VERSION 5.7 ;
  NOWIREEXTENSIONATPIN ON ;
  DIVIDERCHAR "/" ;
  BUSBITCHARS "[]" ;
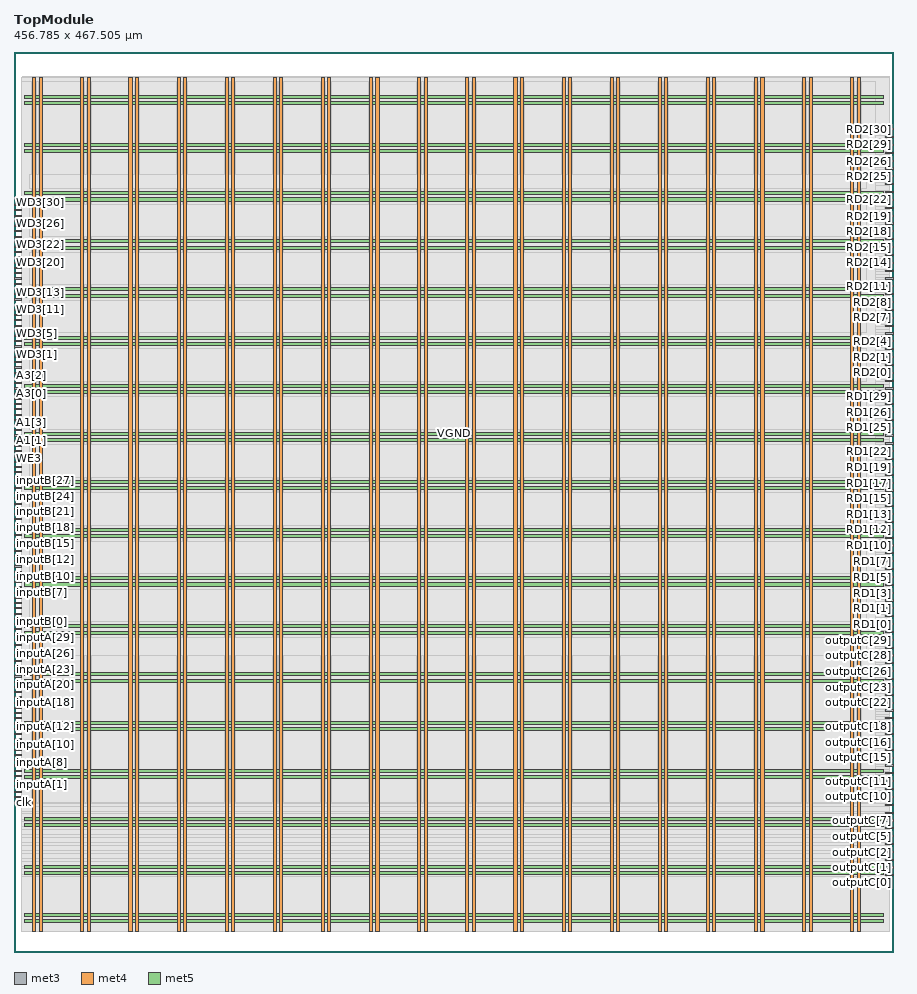
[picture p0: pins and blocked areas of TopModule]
MACRO TopModule
  CLASS BLOCK ;
  FOREIGN TopModule ;
  ORIGIN 0.000 0.000 ;
  SIZE 456.785 BY 467.505 ;
  PIN A1[0]
    DIRECTION INPUT ;
    USE SIGNAL ;
    ANTENNAGATEAREA 2.446500 ;
    PORT
      LAYER met3 ;
        RECT 0.000 262.520 4.000 263.120 ;
    END
  END A1[0]
  PIN A1[1]
    DIRECTION INPUT ;
    USE SIGNAL ;
    ANTENNAGATEAREA 1.560000 ;
    ANTENNADIFFAREA 0.434700 ;
    PORT
      LAYER met3 ;
        RECT 0.000 265.240 4.000 265.840 ;
    END
  END A1[1]
  PIN A1[2]
    DIRECTION INPUT ;
    USE SIGNAL ;
    ANTENNAGATEAREA 0.159000 ;
    PORT
      LAYER met3 ;
        RECT 0.000 267.960 4.000 268.560 ;
    END
  END A1[2]
  PIN A1[3]
    DIRECTION INPUT ;
    USE SIGNAL ;
    ANTENNAGATEAREA 0.247500 ;
    PORT
      LAYER met3 ;
        RECT 0.000 270.680 4.000 271.280 ;
    END
  END A1[3]
  PIN A1[4]
    DIRECTION INPUT ;
    USE SIGNAL ;
    ANTENNAGATEAREA 0.495000 ;
    PORT
      LAYER met3 ;
        RECT 0.000 273.400 4.000 274.000 ;
    END
  END A1[4]
  PIN A2[0]
    DIRECTION INPUT ;
    USE SIGNAL ;
    ANTENNAGATEAREA 0.247500 ;
    PORT
      LAYER met3 ;
        RECT 0.000 276.120 4.000 276.720 ;
    END
  END A2[0]
  PIN A2[1]
    DIRECTION INPUT ;
    USE SIGNAL ;
    ANTENNAGATEAREA 0.213000 ;
    PORT
      LAYER met3 ;
        RECT 0.000 278.840 4.000 279.440 ;
    END
  END A2[1]
  PIN A2[2]
    DIRECTION INPUT ;
    USE SIGNAL ;
    ANTENNAGATEAREA 0.159000 ;
    PORT
      LAYER met3 ;
        RECT 0.000 281.560 4.000 282.160 ;
    END
  END A2[2]
  PIN A2[3]
    DIRECTION INPUT ;
    USE SIGNAL ;
    ANTENNAGATEAREA 0.426000 ;
    PORT
      LAYER met3 ;
        RECT 0.000 284.280 4.000 284.880 ;
    END
  END A2[3]
  PIN A2[4]
    DIRECTION INPUT ;
    USE SIGNAL ;
    ANTENNAGATEAREA 0.495000 ;
    PORT
      LAYER met3 ;
        RECT 0.000 287.000 4.000 287.600 ;
    END
  END A2[4]
  PIN A3[0]
    DIRECTION INPUT ;
    USE SIGNAL ;
    ANTENNAGATEAREA 0.247500 ;
    PORT
      LAYER met3 ;
        RECT 0.000 289.720 4.000 290.320 ;
    END
  END A3[0]
  PIN A3[1]
    DIRECTION INPUT ;
    USE SIGNAL ;
    ANTENNAGATEAREA 0.213000 ;
    PORT
      LAYER met3 ;
        RECT 0.000 292.440 4.000 293.040 ;
    END
  END A3[1]
  PIN A3[2]
    DIRECTION INPUT ;
    USE SIGNAL ;
    ANTENNAGATEAREA 0.213000 ;
    PORT
      LAYER met3 ;
        RECT 0.000 295.160 4.000 295.760 ;
    END
  END A3[2]
  PIN A3[3]
    DIRECTION INPUT ;
    USE SIGNAL ;
    ANTENNAGATEAREA 0.213000 ;
    PORT
      LAYER met3 ;
        RECT 0.000 297.880 4.000 298.480 ;
    END
  END A3[3]
  PIN A3[4]
    DIRECTION INPUT ;
    USE SIGNAL ;
    ANTENNAGATEAREA 0.213000 ;
    PORT
      LAYER met3 ;
        RECT 0.000 300.600 4.000 301.200 ;
    END
  END A3[4]
  PIN RD1[0]
    DIRECTION OUTPUT ;
    USE SIGNAL ;
    ANTENNADIFFAREA 0.445500 ;
    PORT
      LAYER met3 ;
        RECT 452.785 170.040 456.785 170.640 ;
    END
  END RD1[0]
  PIN RD1[10]
    DIRECTION OUTPUT ;
    USE SIGNAL ;
    ANTENNADIFFAREA 0.445500 ;
    PORT
      LAYER met3 ;
        RECT 452.785 210.840 456.785 211.440 ;
    END
  END RD1[10]
  PIN RD1[11]
    DIRECTION OUTPUT ;
    USE SIGNAL ;
    ANTENNADIFFAREA 0.445500 ;
    PORT
      LAYER met3 ;
        RECT 452.785 214.920 456.785 215.520 ;
    END
  END RD1[11]
  PIN RD1[12]
    DIRECTION OUTPUT ;
    USE SIGNAL ;
    ANTENNADIFFAREA 0.445500 ;
    PORT
      LAYER met3 ;
        RECT 452.785 219.000 456.785 219.600 ;
    END
  END RD1[12]
  PIN RD1[13]
    DIRECTION OUTPUT ;
    USE SIGNAL ;
    ANTENNADIFFAREA 0.445500 ;
    PORT
      LAYER met3 ;
        RECT 452.785 223.080 456.785 223.680 ;
    END
  END RD1[13]
  PIN RD1[14]
    DIRECTION OUTPUT ;
    USE SIGNAL ;
    ANTENNADIFFAREA 0.445500 ;
    PORT
      LAYER met3 ;
        RECT 452.785 227.160 456.785 227.760 ;
    END
  END RD1[14]
  PIN RD1[15]
    DIRECTION OUTPUT ;
    USE SIGNAL ;
    ANTENNADIFFAREA 0.445500 ;
    PORT
      LAYER met3 ;
        RECT 452.785 231.240 456.785 231.840 ;
    END
  END RD1[15]
  PIN RD1[16]
    DIRECTION OUTPUT ;
    USE SIGNAL ;
    ANTENNADIFFAREA 0.445500 ;
    PORT
      LAYER met3 ;
        RECT 452.785 235.320 456.785 235.920 ;
    END
  END RD1[16]
  PIN RD1[17]
    DIRECTION OUTPUT ;
    USE SIGNAL ;
    ANTENNADIFFAREA 0.445500 ;
    PORT
      LAYER met3 ;
        RECT 452.785 239.400 456.785 240.000 ;
    END
  END RD1[17]
  PIN RD1[18]
    DIRECTION OUTPUT ;
    USE SIGNAL ;
    ANTENNADIFFAREA 0.445500 ;
    PORT
      LAYER met3 ;
        RECT 452.785 243.480 456.785 244.080 ;
    END
  END RD1[18]
  PIN RD1[19]
    DIRECTION OUTPUT ;
    USE SIGNAL ;
    ANTENNADIFFAREA 0.445500 ;
    PORT
      LAYER met3 ;
        RECT 452.785 247.560 456.785 248.160 ;
    END
  END RD1[19]
  PIN RD1[1]
    DIRECTION OUTPUT ;
    USE SIGNAL ;
    ANTENNADIFFAREA 0.445500 ;
    PORT
      LAYER met3 ;
        RECT 452.785 174.120 456.785 174.720 ;
    END
  END RD1[1]
  PIN RD1[20]
    DIRECTION OUTPUT ;
    USE SIGNAL ;
    ANTENNADIFFAREA 0.445500 ;
    PORT
      LAYER met3 ;
        RECT 452.785 251.640 456.785 252.240 ;
    END
  END RD1[20]
  PIN RD1[21]
    DIRECTION OUTPUT ;
    USE SIGNAL ;
    ANTENNADIFFAREA 0.445500 ;
    PORT
      LAYER met3 ;
        RECT 452.785 255.720 456.785 256.320 ;
    END
  END RD1[21]
  PIN RD1[22]
    DIRECTION OUTPUT ;
    USE SIGNAL ;
    ANTENNADIFFAREA 0.445500 ;
    PORT
      LAYER met3 ;
        RECT 452.785 259.800 456.785 260.400 ;
    END
  END RD1[22]
  PIN RD1[23]
    DIRECTION OUTPUT ;
    USE SIGNAL ;
    ANTENNADIFFAREA 0.445500 ;
    PORT
      LAYER met3 ;
        RECT 452.785 263.880 456.785 264.480 ;
    END
  END RD1[23]
  PIN RD1[24]
    DIRECTION OUTPUT ;
    USE SIGNAL ;
    ANTENNADIFFAREA 0.445500 ;
    PORT
      LAYER met3 ;
        RECT 452.785 267.960 456.785 268.560 ;
    END
  END RD1[24]
  PIN RD1[25]
    DIRECTION OUTPUT ;
    USE SIGNAL ;
    ANTENNADIFFAREA 0.445500 ;
    PORT
      LAYER met3 ;
        RECT 452.785 272.040 456.785 272.640 ;
    END
  END RD1[25]
  PIN RD1[26]
    DIRECTION OUTPUT ;
    USE SIGNAL ;
    ANTENNADIFFAREA 0.445500 ;
    PORT
      LAYER met3 ;
        RECT 452.785 276.120 456.785 276.720 ;
    END
  END RD1[26]
  PIN RD1[27]
    DIRECTION OUTPUT ;
    USE SIGNAL ;
    ANTENNADIFFAREA 0.445500 ;
    PORT
      LAYER met3 ;
        RECT 452.785 280.200 456.785 280.800 ;
    END
  END RD1[27]
  PIN RD1[28]
    DIRECTION OUTPUT ;
    USE SIGNAL ;
    ANTENNADIFFAREA 0.445500 ;
    PORT
      LAYER met3 ;
        RECT 452.785 284.280 456.785 284.880 ;
    END
  END RD1[28]
  PIN RD1[29]
    DIRECTION OUTPUT ;
    USE SIGNAL ;
    ANTENNADIFFAREA 0.445500 ;
    PORT
      LAYER met3 ;
        RECT 452.785 288.360 456.785 288.960 ;
    END
  END RD1[29]
  PIN RD1[2]
    DIRECTION OUTPUT ;
    USE SIGNAL ;
    ANTENNADIFFAREA 0.445500 ;
    PORT
      LAYER met3 ;
        RECT 452.785 178.200 456.785 178.800 ;
    END
  END RD1[2]
  PIN RD1[30]
    DIRECTION OUTPUT ;
    USE SIGNAL ;
    ANTENNADIFFAREA 0.445500 ;
    PORT
      LAYER met3 ;
        RECT 452.785 292.440 456.785 293.040 ;
    END
  END RD1[30]
  PIN RD1[31]
    DIRECTION OUTPUT ;
    USE SIGNAL ;
    ANTENNADIFFAREA 0.445500 ;
    PORT
      LAYER met3 ;
        RECT 452.785 296.520 456.785 297.120 ;
    END
  END RD1[31]
  PIN RD1[3]
    DIRECTION OUTPUT ;
    USE SIGNAL ;
    ANTENNADIFFAREA 0.445500 ;
    PORT
      LAYER met3 ;
        RECT 452.785 182.280 456.785 182.880 ;
    END
  END RD1[3]
  PIN RD1[4]
    DIRECTION OUTPUT ;
    USE SIGNAL ;
    ANTENNADIFFAREA 0.445500 ;
    PORT
      LAYER met3 ;
        RECT 452.785 186.360 456.785 186.960 ;
    END
  END RD1[4]
  PIN RD1[5]
    DIRECTION OUTPUT ;
    USE SIGNAL ;
    ANTENNADIFFAREA 0.445500 ;
    PORT
      LAYER met3 ;
        RECT 452.785 190.440 456.785 191.040 ;
    END
  END RD1[5]
  PIN RD1[6]
    DIRECTION OUTPUT ;
    USE SIGNAL ;
    ANTENNADIFFAREA 0.445500 ;
    PORT
      LAYER met3 ;
        RECT 452.785 194.520 456.785 195.120 ;
    END
  END RD1[6]
  PIN RD1[7]
    DIRECTION OUTPUT ;
    USE SIGNAL ;
    ANTENNADIFFAREA 0.445500 ;
    PORT
      LAYER met3 ;
        RECT 452.785 198.600 456.785 199.200 ;
    END
  END RD1[7]
  PIN RD1[8]
    DIRECTION OUTPUT ;
    USE SIGNAL ;
    ANTENNADIFFAREA 0.445500 ;
    PORT
      LAYER met3 ;
        RECT 452.785 202.680 456.785 203.280 ;
    END
  END RD1[8]
  PIN RD1[9]
    DIRECTION OUTPUT ;
    USE SIGNAL ;
    ANTENNADIFFAREA 0.445500 ;
    PORT
      LAYER met3 ;
        RECT 452.785 206.760 456.785 207.360 ;
    END
  END RD1[9]
  PIN RD2[0]
    DIRECTION OUTPUT ;
    USE SIGNAL ;
    ANTENNADIFFAREA 0.445500 ;
    PORT
      LAYER met3 ;
        RECT 452.785 300.600 456.785 301.200 ;
    END
  END RD2[0]
  PIN RD2[10]
    DIRECTION OUTPUT ;
    USE SIGNAL ;
    ANTENNADIFFAREA 0.445500 ;
    PORT
      LAYER met3 ;
        RECT 452.785 341.400 456.785 342.000 ;
    END
  END RD2[10]
  PIN RD2[11]
    DIRECTION OUTPUT ;
    USE SIGNAL ;
    ANTENNADIFFAREA 0.445500 ;
    PORT
      LAYER met3 ;
        RECT 452.785 345.480 456.785 346.080 ;
    END
  END RD2[11]
  PIN RD2[12]
    DIRECTION OUTPUT ;
    USE SIGNAL ;
    ANTENNADIFFAREA 0.445500 ;
    PORT
      LAYER met3 ;
        RECT 452.785 349.560 456.785 350.160 ;
    END
  END RD2[12]
  PIN RD2[13]
    DIRECTION OUTPUT ;
    USE SIGNAL ;
    ANTENNADIFFAREA 0.445500 ;
    PORT
      LAYER met3 ;
        RECT 452.785 353.640 456.785 354.240 ;
    END
  END RD2[13]
  PIN RD2[14]
    DIRECTION OUTPUT ;
    USE SIGNAL ;
    ANTENNADIFFAREA 0.445500 ;
    PORT
      LAYER met3 ;
        RECT 452.785 357.720 456.785 358.320 ;
    END
  END RD2[14]
  PIN RD2[15]
    DIRECTION OUTPUT ;
    USE SIGNAL ;
    ANTENNADIFFAREA 0.445500 ;
    PORT
      LAYER met3 ;
        RECT 452.785 361.800 456.785 362.400 ;
    END
  END RD2[15]
  PIN RD2[16]
    DIRECTION OUTPUT ;
    USE SIGNAL ;
    ANTENNADIFFAREA 0.445500 ;
    PORT
      LAYER met3 ;
        RECT 452.785 365.880 456.785 366.480 ;
    END
  END RD2[16]
  PIN RD2[17]
    DIRECTION OUTPUT ;
    USE SIGNAL ;
    ANTENNADIFFAREA 0.445500 ;
    PORT
      LAYER met3 ;
        RECT 452.785 369.960 456.785 370.560 ;
    END
  END RD2[17]
  PIN RD2[18]
    DIRECTION OUTPUT ;
    USE SIGNAL ;
    ANTENNADIFFAREA 0.445500 ;
    PORT
      LAYER met3 ;
        RECT 452.785 374.040 456.785 374.640 ;
    END
  END RD2[18]
  PIN RD2[19]
    DIRECTION OUTPUT ;
    USE SIGNAL ;
    ANTENNADIFFAREA 0.445500 ;
    PORT
      LAYER met3 ;
        RECT 452.785 378.120 456.785 378.720 ;
    END
  END RD2[19]
  PIN RD2[1]
    DIRECTION OUTPUT ;
    USE SIGNAL ;
    ANTENNADIFFAREA 0.445500 ;
    PORT
      LAYER met3 ;
        RECT 452.785 304.680 456.785 305.280 ;
    END
  END RD2[1]
  PIN RD2[20]
    DIRECTION OUTPUT ;
    USE SIGNAL ;
    ANTENNADIFFAREA 0.445500 ;
    PORT
      LAYER met3 ;
        RECT 452.785 382.200 456.785 382.800 ;
    END
  END RD2[20]
  PIN RD2[21]
    DIRECTION OUTPUT ;
    USE SIGNAL ;
    ANTENNADIFFAREA 0.445500 ;
    PORT
      LAYER met3 ;
        RECT 452.785 386.280 456.785 386.880 ;
    END
  END RD2[21]
  PIN RD2[22]
    DIRECTION OUTPUT ;
    USE SIGNAL ;
    ANTENNADIFFAREA 0.445500 ;
    PORT
      LAYER met3 ;
        RECT 452.785 390.360 456.785 390.960 ;
    END
  END RD2[22]
  PIN RD2[23]
    DIRECTION OUTPUT ;
    USE SIGNAL ;
    ANTENNADIFFAREA 0.445500 ;
    PORT
      LAYER met3 ;
        RECT 452.785 394.440 456.785 395.040 ;
    END
  END RD2[23]
  PIN RD2[24]
    DIRECTION OUTPUT ;
    USE SIGNAL ;
    ANTENNADIFFAREA 0.445500 ;
    PORT
      LAYER met3 ;
        RECT 452.785 398.520 456.785 399.120 ;
    END
  END RD2[24]
  PIN RD2[25]
    DIRECTION OUTPUT ;
    USE SIGNAL ;
    ANTENNADIFFAREA 0.445500 ;
    PORT
      LAYER met3 ;
        RECT 452.785 402.600 456.785 403.200 ;
    END
  END RD2[25]
  PIN RD2[26]
    DIRECTION OUTPUT ;
    USE SIGNAL ;
    ANTENNADIFFAREA 0.445500 ;
    PORT
      LAYER met3 ;
        RECT 452.785 406.680 456.785 407.280 ;
    END
  END RD2[26]
  PIN RD2[27]
    DIRECTION OUTPUT ;
    USE SIGNAL ;
    ANTENNADIFFAREA 0.445500 ;
    PORT
      LAYER met3 ;
        RECT 452.785 410.760 456.785 411.360 ;
    END
  END RD2[27]
  PIN RD2[28]
    DIRECTION OUTPUT ;
    USE SIGNAL ;
    ANTENNADIFFAREA 0.445500 ;
    PORT
      LAYER met3 ;
        RECT 452.785 414.840 456.785 415.440 ;
    END
  END RD2[28]
  PIN RD2[29]
    DIRECTION OUTPUT ;
    USE SIGNAL ;
    ANTENNADIFFAREA 0.445500 ;
    PORT
      LAYER met3 ;
        RECT 452.785 418.920 456.785 419.520 ;
    END
  END RD2[29]
  PIN RD2[2]
    DIRECTION OUTPUT ;
    USE SIGNAL ;
    ANTENNADIFFAREA 0.445500 ;
    PORT
      LAYER met3 ;
        RECT 452.785 308.760 456.785 309.360 ;
    END
  END RD2[2]
  PIN RD2[30]
    DIRECTION OUTPUT ;
    USE SIGNAL ;
    ANTENNADIFFAREA 0.445500 ;
    PORT
      LAYER met3 ;
        RECT 452.785 423.000 456.785 423.600 ;
    END
  END RD2[30]
  PIN RD2[31]
    DIRECTION OUTPUT ;
    USE SIGNAL ;
    ANTENNADIFFAREA 0.445500 ;
    PORT
      LAYER met3 ;
        RECT 452.785 427.080 456.785 427.680 ;
    END
  END RD2[31]
  PIN RD2[3]
    DIRECTION OUTPUT ;
    USE SIGNAL ;
    ANTENNADIFFAREA 0.445500 ;
    PORT
      LAYER met3 ;
        RECT 452.785 312.840 456.785 313.440 ;
    END
  END RD2[3]
  PIN RD2[4]
    DIRECTION OUTPUT ;
    USE SIGNAL ;
    ANTENNADIFFAREA 0.445500 ;
    PORT
      LAYER met3 ;
        RECT 452.785 316.920 456.785 317.520 ;
    END
  END RD2[4]
  PIN RD2[5]
    DIRECTION OUTPUT ;
    USE SIGNAL ;
    ANTENNADIFFAREA 0.445500 ;
    PORT
      LAYER met3 ;
        RECT 452.785 321.000 456.785 321.600 ;
    END
  END RD2[5]
  PIN RD2[6]
    DIRECTION OUTPUT ;
    USE SIGNAL ;
    ANTENNADIFFAREA 0.445500 ;
    PORT
      LAYER met3 ;
        RECT 452.785 325.080 456.785 325.680 ;
    END
  END RD2[6]
  PIN RD2[7]
    DIRECTION OUTPUT ;
    USE SIGNAL ;
    ANTENNADIFFAREA 0.445500 ;
    PORT
      LAYER met3 ;
        RECT 452.785 329.160 456.785 329.760 ;
    END
  END RD2[7]
  PIN RD2[8]
    DIRECTION OUTPUT ;
    USE SIGNAL ;
    ANTENNADIFFAREA 0.445500 ;
    PORT
      LAYER met3 ;
        RECT 452.785 333.240 456.785 333.840 ;
    END
  END RD2[8]
  PIN RD2[9]
    DIRECTION OUTPUT ;
    USE SIGNAL ;
    ANTENNADIFFAREA 0.445500 ;
    PORT
      LAYER met3 ;
        RECT 452.785 337.320 456.785 337.920 ;
    END
  END RD2[9]
  PIN VGND
    DIRECTION INOUT ;
    USE GROUND ;
    PORT
      LAYER met4 ;
        RECT 13.020 10.640 14.620 454.480 ;
    END
    PORT
      LAYER met4 ;
        RECT 38.020 10.640 39.620 454.480 ;
    END
    PORT
      LAYER met4 ;
        RECT 63.020 10.640 64.620 454.480 ;
    END
    PORT
      LAYER met4 ;
        RECT 88.020 10.640 89.620 454.480 ;
    END
    PORT
      LAYER met4 ;
        RECT 113.020 10.640 114.620 454.480 ;
    END
    PORT
      LAYER met4 ;
        RECT 138.020 10.640 139.620 454.480 ;
    END
    PORT
      LAYER met4 ;
        RECT 163.020 10.640 164.620 454.480 ;
    END
    PORT
      LAYER met4 ;
        RECT 188.020 10.640 189.620 454.480 ;
    END
    PORT
      LAYER met4 ;
        RECT 213.020 10.640 214.620 454.480 ;
    END
    PORT
      LAYER met4 ;
        RECT 238.020 10.640 239.620 454.480 ;
    END
    PORT
      LAYER met4 ;
        RECT 263.020 10.640 264.620 454.480 ;
    END
    PORT
      LAYER met4 ;
        RECT 288.020 10.640 289.620 454.480 ;
    END
    PORT
      LAYER met4 ;
        RECT 313.020 10.640 314.620 454.480 ;
    END
    PORT
      LAYER met4 ;
        RECT 338.020 10.640 339.620 454.480 ;
    END
    PORT
      LAYER met4 ;
        RECT 363.020 10.640 364.620 454.480 ;
    END
    PORT
      LAYER met4 ;
        RECT 388.020 10.640 389.620 454.480 ;
    END
    PORT
      LAYER met4 ;
        RECT 413.020 10.640 414.620 454.480 ;
    END
    PORT
      LAYER met4 ;
        RECT 438.020 10.640 439.620 454.480 ;
    END
    PORT
      LAYER met5 ;
        RECT 5.280 18.380 451.500 19.980 ;
    END
    PORT
      LAYER met5 ;
        RECT 5.280 43.380 451.500 44.980 ;
    END
    PORT
      LAYER met5 ;
        RECT 5.280 68.380 451.500 69.980 ;
    END
    PORT
      LAYER met5 ;
        RECT 5.280 93.380 451.500 94.980 ;
    END
    PORT
      LAYER met5 ;
        RECT 5.280 118.380 451.500 119.980 ;
    END
    PORT
      LAYER met5 ;
        RECT 5.280 143.380 451.500 144.980 ;
    END
    PORT
      LAYER met5 ;
        RECT 5.280 168.380 451.500 169.980 ;
    END
    PORT
      LAYER met5 ;
        RECT 5.280 193.380 451.500 194.980 ;
    END
    PORT
      LAYER met5 ;
        RECT 5.280 218.380 451.500 219.980 ;
    END
    PORT
      LAYER met5 ;
        RECT 5.280 243.380 451.500 244.980 ;
    END
    PORT
      LAYER met5 ;
        RECT 5.280 268.380 451.500 269.980 ;
    END
    PORT
      LAYER met5 ;
        RECT 5.280 293.380 451.500 294.980 ;
    END
    PORT
      LAYER met5 ;
        RECT 5.280 318.380 451.500 319.980 ;
    END
    PORT
      LAYER met5 ;
        RECT 5.280 343.380 451.500 344.980 ;
    END
    PORT
      LAYER met5 ;
        RECT 5.280 368.380 451.500 369.980 ;
    END
    PORT
      LAYER met5 ;
        RECT 5.280 393.380 451.500 394.980 ;
    END
    PORT
      LAYER met5 ;
        RECT 5.280 418.380 451.500 419.980 ;
    END
    PORT
      LAYER met5 ;
        RECT 5.280 443.380 451.500 444.980 ;
    END
  END VGND
  PIN VPWR
    DIRECTION INOUT ;
    USE POWER ;
    PORT
      LAYER met4 ;
        RECT 9.720 10.640 11.320 454.480 ;
    END
    PORT
      LAYER met4 ;
        RECT 34.720 10.640 36.320 454.480 ;
    END
    PORT
      LAYER met4 ;
        RECT 59.720 10.640 61.320 454.480 ;
    END
    PORT
      LAYER met4 ;
        RECT 84.720 10.640 86.320 454.480 ;
    END
    PORT
      LAYER met4 ;
        RECT 109.720 10.640 111.320 454.480 ;
    END
    PORT
      LAYER met4 ;
        RECT 134.720 10.640 136.320 454.480 ;
    END
    PORT
      LAYER met4 ;
        RECT 159.720 10.640 161.320 454.480 ;
    END
    PORT
      LAYER met4 ;
        RECT 184.720 10.640 186.320 454.480 ;
    END
    PORT
      LAYER met4 ;
        RECT 209.720 10.640 211.320 454.480 ;
    END
    PORT
      LAYER met4 ;
        RECT 234.720 10.640 236.320 454.480 ;
    END
    PORT
      LAYER met4 ;
        RECT 259.720 10.640 261.320 454.480 ;
    END
    PORT
      LAYER met4 ;
        RECT 284.720 10.640 286.320 454.480 ;
    END
    PORT
      LAYER met4 ;
        RECT 309.720 10.640 311.320 454.480 ;
    END
    PORT
      LAYER met4 ;
        RECT 334.720 10.640 336.320 454.480 ;
    END
    PORT
      LAYER met4 ;
        RECT 359.720 10.640 361.320 454.480 ;
    END
    PORT
      LAYER met4 ;
        RECT 384.720 10.640 386.320 454.480 ;
    END
    PORT
      LAYER met4 ;
        RECT 409.720 10.640 411.320 454.480 ;
    END
    PORT
      LAYER met4 ;
        RECT 434.720 10.640 436.320 454.480 ;
    END
    PORT
      LAYER met5 ;
        RECT 5.280 15.080 451.500 16.680 ;
    END
    PORT
      LAYER met5 ;
        RECT 5.280 40.080 451.500 41.680 ;
    END
    PORT
      LAYER met5 ;
        RECT 5.280 65.080 451.500 66.680 ;
    END
    PORT
      LAYER met5 ;
        RECT 5.280 90.080 451.500 91.680 ;
    END
    PORT
      LAYER met5 ;
        RECT 5.280 115.080 451.500 116.680 ;
    END
    PORT
      LAYER met5 ;
        RECT 5.280 140.080 451.500 141.680 ;
    END
    PORT
      LAYER met5 ;
        RECT 5.280 165.080 451.500 166.680 ;
    END
    PORT
      LAYER met5 ;
        RECT 5.280 190.080 451.500 191.680 ;
    END
    PORT
      LAYER met5 ;
        RECT 5.280 215.080 451.500 216.680 ;
    END
    PORT
      LAYER met5 ;
        RECT 5.280 240.080 451.500 241.680 ;
    END
    PORT
      LAYER met5 ;
        RECT 5.280 265.080 451.500 266.680 ;
    END
    PORT
      LAYER met5 ;
        RECT 5.280 290.080 451.500 291.680 ;
    END
    PORT
      LAYER met5 ;
        RECT 5.280 315.080 451.500 316.680 ;
    END
    PORT
      LAYER met5 ;
        RECT 5.280 340.080 451.500 341.680 ;
    END
    PORT
      LAYER met5 ;
        RECT 5.280 365.080 451.500 366.680 ;
    END
    PORT
      LAYER met5 ;
        RECT 5.280 390.080 451.500 391.680 ;
    END
    PORT
      LAYER met5 ;
        RECT 5.280 415.080 451.500 416.680 ;
    END
    PORT
      LAYER met5 ;
        RECT 5.280 440.080 451.500 441.680 ;
    END
  END VPWR
  PIN WD3[0]
    DIRECTION INPUT ;
    USE SIGNAL ;
    ANTENNAGATEAREA 0.213000 ;
    PORT
      LAYER met3 ;
        RECT 0.000 303.320 4.000 303.920 ;
    END
  END WD3[0]
  PIN WD3[10]
    DIRECTION INPUT ;
    USE SIGNAL ;
    ANTENNAGATEAREA 0.159000 ;
    PORT
      LAYER met3 ;
        RECT 0.000 330.520 4.000 331.120 ;
    END
  END WD3[10]
  PIN WD3[11]
    DIRECTION INPUT ;
    USE SIGNAL ;
    ANTENNAGATEAREA 0.159000 ;
    PORT
      LAYER met3 ;
        RECT 0.000 333.240 4.000 333.840 ;
    END
  END WD3[11]
  PIN WD3[12]
    DIRECTION INPUT ;
    USE SIGNAL ;
    ANTENNAGATEAREA 0.213000 ;
    PORT
      LAYER met3 ;
        RECT 0.000 335.960 4.000 336.560 ;
    END
  END WD3[12]
  PIN WD3[13]
    DIRECTION INPUT ;
    USE SIGNAL ;
    ANTENNAGATEAREA 0.159000 ;
    PORT
      LAYER met3 ;
        RECT 0.000 338.680 4.000 339.280 ;
    END
  END WD3[13]
  PIN WD3[14]
    DIRECTION INPUT ;
    USE SIGNAL ;
    ANTENNAGATEAREA 0.159000 ;
    PORT
      LAYER met3 ;
        RECT 0.000 341.400 4.000 342.000 ;
    END
  END WD3[14]
  PIN WD3[15]
    DIRECTION INPUT ;
    USE SIGNAL ;
    ANTENNAGATEAREA 0.159000 ;
    PORT
      LAYER met3 ;
        RECT 0.000 344.120 4.000 344.720 ;
    END
  END WD3[15]
  PIN WD3[16]
    DIRECTION INPUT ;
    USE SIGNAL ;
    ANTENNAGATEAREA 0.159000 ;
    PORT
      LAYER met3 ;
        RECT 0.000 346.840 4.000 347.440 ;
    END
  END WD3[16]
  PIN WD3[17]
    DIRECTION INPUT ;
    USE SIGNAL ;
    ANTENNAGATEAREA 0.213000 ;
    PORT
      LAYER met3 ;
        RECT 0.000 349.560 4.000 350.160 ;
    END
  END WD3[17]
  PIN WD3[18]
    DIRECTION INPUT ;
    USE SIGNAL ;
    ANTENNAGATEAREA 0.159000 ;
    PORT
      LAYER met3 ;
        RECT 0.000 352.280 4.000 352.880 ;
    END
  END WD3[18]
  PIN WD3[19]
    DIRECTION INPUT ;
    USE SIGNAL ;
    ANTENNAGATEAREA 0.213000 ;
    PORT
      LAYER met3 ;
        RECT 0.000 355.000 4.000 355.600 ;
    END
  END WD3[19]
  PIN WD3[1]
    DIRECTION INPUT ;
    USE SIGNAL ;
    ANTENNAGATEAREA 0.213000 ;
    PORT
      LAYER met3 ;
        RECT 0.000 306.040 4.000 306.640 ;
    END
  END WD3[1]
  PIN WD3[20]
    DIRECTION INPUT ;
    USE SIGNAL ;
    ANTENNAGATEAREA 0.159000 ;
    PORT
      LAYER met3 ;
        RECT 0.000 357.720 4.000 358.320 ;
    END
  END WD3[20]
  PIN WD3[21]
    DIRECTION INPUT ;
    USE SIGNAL ;
    ANTENNAGATEAREA 0.213000 ;
    PORT
      LAYER met3 ;
        RECT 0.000 360.440 4.000 361.040 ;
    END
  END WD3[21]
  PIN WD3[22]
    DIRECTION INPUT ;
    USE SIGNAL ;
    ANTENNAGATEAREA 0.159000 ;
    PORT
      LAYER met3 ;
        RECT 0.000 363.160 4.000 363.760 ;
    END
  END WD3[22]
  PIN WD3[23]
    DIRECTION INPUT ;
    USE SIGNAL ;
    ANTENNAGATEAREA 0.213000 ;
    PORT
      LAYER met3 ;
        RECT 0.000 365.880 4.000 366.480 ;
    END
  END WD3[23]
  PIN WD3[24]
    DIRECTION INPUT ;
    USE SIGNAL ;
    ANTENNAGATEAREA 0.213000 ;
    PORT
      LAYER met3 ;
        RECT 0.000 368.600 4.000 369.200 ;
    END
  END WD3[24]
  PIN WD3[25]
    DIRECTION INPUT ;
    USE SIGNAL ;
    ANTENNAGATEAREA 0.159000 ;
    PORT
      LAYER met3 ;
        RECT 0.000 371.320 4.000 371.920 ;
    END
  END WD3[25]
  PIN WD3[26]
    DIRECTION INPUT ;
    USE SIGNAL ;
    ANTENNAGATEAREA 0.159000 ;
    PORT
      LAYER met3 ;
        RECT 0.000 374.040 4.000 374.640 ;
    END
  END WD3[26]
  PIN WD3[27]
    DIRECTION INPUT ;
    USE SIGNAL ;
    ANTENNAGATEAREA 0.159000 ;
    PORT
      LAYER met3 ;
        RECT 0.000 376.760 4.000 377.360 ;
    END
  END WD3[27]
  PIN WD3[28]
    DIRECTION INPUT ;
    USE SIGNAL ;
    ANTENNAGATEAREA 0.159000 ;
    PORT
      LAYER met3 ;
        RECT 0.000 379.480 4.000 380.080 ;
    END
  END WD3[28]
  PIN WD3[29]
    DIRECTION INPUT ;
    USE SIGNAL ;
    ANTENNAGATEAREA 0.159000 ;
    PORT
      LAYER met3 ;
        RECT 0.000 382.200 4.000 382.800 ;
    END
  END WD3[29]
  PIN WD3[2]
    DIRECTION INPUT ;
    USE SIGNAL ;
    ANTENNAGATEAREA 0.213000 ;
    PORT
      LAYER met3 ;
        RECT 0.000 308.760 4.000 309.360 ;
    END
  END WD3[2]
  PIN WD3[30]
    DIRECTION INPUT ;
    USE SIGNAL ;
    ANTENNAGATEAREA 0.159000 ;
    PORT
      LAYER met3 ;
        RECT 0.000 384.920 4.000 385.520 ;
    END
  END WD3[30]
  PIN WD3[31]
    DIRECTION INPUT ;
    USE SIGNAL ;
    ANTENNAGATEAREA 0.213000 ;
    PORT
      LAYER met3 ;
        RECT 0.000 387.640 4.000 388.240 ;
    END
  END WD3[31]
  PIN WD3[3]
    DIRECTION INPUT ;
    USE SIGNAL ;
    ANTENNAGATEAREA 0.213000 ;
    PORT
      LAYER met3 ;
        RECT 0.000 311.480 4.000 312.080 ;
    END
  END WD3[3]
  PIN WD3[4]
    DIRECTION INPUT ;
    USE SIGNAL ;
    ANTENNAGATEAREA 0.213000 ;
    PORT
      LAYER met3 ;
        RECT 0.000 314.200 4.000 314.800 ;
    END
  END WD3[4]
  PIN WD3[5]
    DIRECTION INPUT ;
    USE SIGNAL ;
    ANTENNAGATEAREA 0.213000 ;
    PORT
      LAYER met3 ;
        RECT 0.000 316.920 4.000 317.520 ;
    END
  END WD3[5]
  PIN WD3[6]
    DIRECTION INPUT ;
    USE SIGNAL ;
    ANTENNAGATEAREA 0.213000 ;
    PORT
      LAYER met3 ;
        RECT 0.000 319.640 4.000 320.240 ;
    END
  END WD3[6]
  PIN WD3[7]
    DIRECTION INPUT ;
    USE SIGNAL ;
    ANTENNAGATEAREA 0.213000 ;
    PORT
      LAYER met3 ;
        RECT 0.000 322.360 4.000 322.960 ;
    END
  END WD3[7]
  PIN WD3[8]
    DIRECTION INPUT ;
    USE SIGNAL ;
    ANTENNAGATEAREA 0.159000 ;
    PORT
      LAYER met3 ;
        RECT 0.000 325.080 4.000 325.680 ;
    END
  END WD3[8]
  PIN WD3[9]
    DIRECTION INPUT ;
    USE SIGNAL ;
    ANTENNAGATEAREA 0.213000 ;
    PORT
      LAYER met3 ;
        RECT 0.000 327.800 4.000 328.400 ;
    END
  END WD3[9]
  PIN WE3
    DIRECTION INPUT ;
    USE SIGNAL ;
    ANTENNAGATEAREA 0.247500 ;
    PORT
      LAYER met3 ;
        RECT 0.000 259.800 4.000 260.400 ;
    END
  END WE3
  PIN clk
    DIRECTION INPUT ;
    USE SIGNAL ;
    ANTENNAGATEAREA 0.852000 ;
    PORT
      LAYER met3 ;
        RECT 0.000 77.560 4.000 78.160 ;
    END
  END clk
  PIN inputA[0]
    DIRECTION INPUT ;
    USE SIGNAL ;
    ANTENNAGATEAREA 0.196500 ;
    PORT
      LAYER met3 ;
        RECT 0.000 80.280 4.000 80.880 ;
    END
  END inputA[0]
  PIN inputA[10]
    DIRECTION INPUT ;
    USE SIGNAL ;
    ANTENNAGATEAREA 0.213000 ;
    PORT
      LAYER met3 ;
        RECT 0.000 107.480 4.000 108.080 ;
    END
  END inputA[10]
  PIN inputA[11]
    DIRECTION INPUT ;
    USE SIGNAL ;
    ANTENNAGATEAREA 0.126000 ;
    PORT
      LAYER met3 ;
        RECT 0.000 110.200 4.000 110.800 ;
    END
  END inputA[11]
  PIN inputA[12]
    DIRECTION INPUT ;
    USE SIGNAL ;
    ANTENNAGATEAREA 0.213000 ;
    PORT
      LAYER met3 ;
        RECT 0.000 112.920 4.000 113.520 ;
    END
  END inputA[12]
  PIN inputA[13]
    DIRECTION INPUT ;
    USE SIGNAL ;
    ANTENNAGATEAREA 0.213000 ;
    PORT
      LAYER met3 ;
        RECT 0.000 115.640 4.000 116.240 ;
    END
  END inputA[13]
  PIN inputA[14]
    DIRECTION INPUT ;
    USE SIGNAL ;
    ANTENNAGATEAREA 0.213000 ;
    PORT
      LAYER met3 ;
        RECT 0.000 118.360 4.000 118.960 ;
    END
  END inputA[14]
  PIN inputA[15]
    DIRECTION INPUT ;
    USE SIGNAL ;
    ANTENNAGATEAREA 0.213000 ;
    PORT
      LAYER met3 ;
        RECT 0.000 121.080 4.000 121.680 ;
    END
  END inputA[15]
  PIN inputA[16]
    DIRECTION INPUT ;
    USE SIGNAL ;
    ANTENNAGATEAREA 0.196500 ;
    PORT
      LAYER met3 ;
        RECT 0.000 123.800 4.000 124.400 ;
    END
  END inputA[16]
  PIN inputA[17]
    DIRECTION INPUT ;
    USE SIGNAL ;
    ANTENNAGATEAREA 0.196500 ;
    PORT
      LAYER met3 ;
        RECT 0.000 126.520 4.000 127.120 ;
    END
  END inputA[17]
  PIN inputA[18]
    DIRECTION INPUT ;
    USE SIGNAL ;
    ANTENNAGATEAREA 0.196500 ;
    PORT
      LAYER met3 ;
        RECT 0.000 129.240 4.000 129.840 ;
    END
  END inputA[18]
  PIN inputA[19]
    DIRECTION INPUT ;
    USE SIGNAL ;
    ANTENNAGATEAREA 0.213000 ;
    PORT
      LAYER met3 ;
        RECT 0.000 131.960 4.000 132.560 ;
    END
  END inputA[19]
  PIN inputA[1]
    DIRECTION INPUT ;
    USE SIGNAL ;
    ANTENNAGATEAREA 0.196500 ;
    PORT
      LAYER met3 ;
        RECT 0.000 83.000 4.000 83.600 ;
    END
  END inputA[1]
  PIN inputA[20]
    DIRECTION INPUT ;
    USE SIGNAL ;
    ANTENNAGATEAREA 0.126000 ;
    PORT
      LAYER met3 ;
        RECT 0.000 134.680 4.000 135.280 ;
    END
  END inputA[20]
  PIN inputA[21]
    DIRECTION INPUT ;
    USE SIGNAL ;
    ANTENNAGATEAREA 0.126000 ;
    PORT
      LAYER met3 ;
        RECT 0.000 137.400 4.000 138.000 ;
    END
  END inputA[21]
  PIN inputA[22]
    DIRECTION INPUT ;
    USE SIGNAL ;
    ANTENNAGATEAREA 0.213000 ;
    PORT
      LAYER met3 ;
        RECT 0.000 140.120 4.000 140.720 ;
    END
  END inputA[22]
  PIN inputA[23]
    DIRECTION INPUT ;
    USE SIGNAL ;
    ANTENNAGATEAREA 0.126000 ;
    PORT
      LAYER met3 ;
        RECT 0.000 142.840 4.000 143.440 ;
    END
  END inputA[23]
  PIN inputA[24]
    DIRECTION INPUT ;
    USE SIGNAL ;
    ANTENNAGATEAREA 0.196500 ;
    PORT
      LAYER met3 ;
        RECT 0.000 145.560 4.000 146.160 ;
    END
  END inputA[24]
  PIN inputA[25]
    DIRECTION INPUT ;
    USE SIGNAL ;
    ANTENNAGATEAREA 0.196500 ;
    PORT
      LAYER met3 ;
        RECT 0.000 148.280 4.000 148.880 ;
    END
  END inputA[25]
  PIN inputA[26]
    DIRECTION INPUT ;
    USE SIGNAL ;
    ANTENNAGATEAREA 0.196500 ;
    PORT
      LAYER met3 ;
        RECT 0.000 151.000 4.000 151.600 ;
    END
  END inputA[26]
  PIN inputA[27]
    DIRECTION INPUT ;
    USE SIGNAL ;
    ANTENNAGATEAREA 0.213000 ;
    PORT
      LAYER met3 ;
        RECT 0.000 153.720 4.000 154.320 ;
    END
  END inputA[27]
  PIN inputA[28]
    DIRECTION INPUT ;
    USE SIGNAL ;
    ANTENNAGATEAREA 0.196500 ;
    PORT
      LAYER met3 ;
        RECT 0.000 156.440 4.000 157.040 ;
    END
  END inputA[28]
  PIN inputA[29]
    DIRECTION INPUT ;
    USE SIGNAL ;
    ANTENNAGATEAREA 0.213000 ;
    PORT
      LAYER met3 ;
        RECT 0.000 159.160 4.000 159.760 ;
    END
  END inputA[29]
  PIN inputA[2]
    DIRECTION INPUT ;
    USE SIGNAL ;
    ANTENNAGATEAREA 0.196500 ;
    PORT
      LAYER met3 ;
        RECT 0.000 85.720 4.000 86.320 ;
    END
  END inputA[2]
  PIN inputA[30]
    DIRECTION INPUT ;
    USE SIGNAL ;
    ANTENNAGATEAREA 0.196500 ;
    PORT
      LAYER met3 ;
        RECT 0.000 161.880 4.000 162.480 ;
    END
  END inputA[30]
  PIN inputA[31]
    DIRECTION INPUT ;
    USE SIGNAL ;
    ANTENNAGATEAREA 0.126000 ;
    PORT
      LAYER met3 ;
        RECT 0.000 164.600 4.000 165.200 ;
    END
  END inputA[31]
  PIN inputA[3]
    DIRECTION INPUT ;
    USE SIGNAL ;
    ANTENNAGATEAREA 0.196500 ;
    PORT
      LAYER met3 ;
        RECT 0.000 88.440 4.000 89.040 ;
    END
  END inputA[3]
  PIN inputA[4]
    DIRECTION INPUT ;
    USE SIGNAL ;
    ANTENNAGATEAREA 0.126000 ;
    PORT
      LAYER met3 ;
        RECT 0.000 91.160 4.000 91.760 ;
    END
  END inputA[4]
  PIN inputA[5]
    DIRECTION INPUT ;
    USE SIGNAL ;
    ANTENNAGATEAREA 0.126000 ;
    PORT
      LAYER met3 ;
        RECT 0.000 93.880 4.000 94.480 ;
    END
  END inputA[5]
  PIN inputA[6]
    DIRECTION INPUT ;
    USE SIGNAL ;
    ANTENNAGATEAREA 0.196500 ;
    PORT
      LAYER met3 ;
        RECT 0.000 96.600 4.000 97.200 ;
    END
  END inputA[6]
  PIN inputA[7]
    DIRECTION INPUT ;
    USE SIGNAL ;
    ANTENNAGATEAREA 0.196500 ;
    PORT
      LAYER met3 ;
        RECT 0.000 99.320 4.000 99.920 ;
    END
  END inputA[7]
  PIN inputA[8]
    DIRECTION INPUT ;
    USE SIGNAL ;
    ANTENNAGATEAREA 0.196500 ;
    PORT
      LAYER met3 ;
        RECT 0.000 102.040 4.000 102.640 ;
    END
  END inputA[8]
  PIN inputA[9]
    DIRECTION INPUT ;
    USE SIGNAL ;
    ANTENNAGATEAREA 0.196500 ;
    PORT
      LAYER met3 ;
        RECT 0.000 104.760 4.000 105.360 ;
    END
  END inputA[9]
  PIN inputB[0]
    DIRECTION INPUT ;
    USE SIGNAL ;
    ANTENNAGATEAREA 0.196500 ;
    PORT
      LAYER met3 ;
        RECT 0.000 167.320 4.000 167.920 ;
    END
  END inputB[0]
  PIN inputB[10]
    DIRECTION INPUT ;
    USE SIGNAL ;
    ANTENNAGATEAREA 0.196500 ;
    PORT
      LAYER met3 ;
        RECT 0.000 194.520 4.000 195.120 ;
    END
  END inputB[10]
  PIN inputB[11]
    DIRECTION INPUT ;
    USE SIGNAL ;
    ANTENNAGATEAREA 0.196500 ;
    PORT
      LAYER met3 ;
        RECT 0.000 197.240 4.000 197.840 ;
    END
  END inputB[11]
  PIN inputB[12]
    DIRECTION INPUT ;
    USE SIGNAL ;
    ANTENNAGATEAREA 0.126000 ;
    PORT
      LAYER met3 ;
        RECT 0.000 199.960 4.000 200.560 ;
    END
  END inputB[12]
  PIN inputB[13]
    DIRECTION INPUT ;
    USE SIGNAL ;
    ANTENNAGATEAREA 0.126000 ;
    PORT
      LAYER met3 ;
        RECT 0.000 202.680 4.000 203.280 ;
    END
  END inputB[13]
  PIN inputB[14]
    DIRECTION INPUT ;
    USE SIGNAL ;
    ANTENNAGATEAREA 0.196500 ;
    PORT
      LAYER met3 ;
        RECT 0.000 205.400 4.000 206.000 ;
    END
  END inputB[14]
  PIN inputB[15]
    DIRECTION INPUT ;
    USE SIGNAL ;
    ANTENNAGATEAREA 0.126000 ;
    PORT
      LAYER met3 ;
        RECT 0.000 208.120 4.000 208.720 ;
    END
  END inputB[15]
  PIN inputB[16]
    DIRECTION INPUT ;
    USE SIGNAL ;
    ANTENNAGATEAREA 0.196500 ;
    PORT
      LAYER met3 ;
        RECT 0.000 210.840 4.000 211.440 ;
    END
  END inputB[16]
  PIN inputB[17]
    DIRECTION INPUT ;
    USE SIGNAL ;
    ANTENNAGATEAREA 0.126000 ;
    PORT
      LAYER met3 ;
        RECT 0.000 213.560 4.000 214.160 ;
    END
  END inputB[17]
  PIN inputB[18]
    DIRECTION INPUT ;
    USE SIGNAL ;
    ANTENNAGATEAREA 0.196500 ;
    PORT
      LAYER met3 ;
        RECT 0.000 216.280 4.000 216.880 ;
    END
  END inputB[18]
  PIN inputB[19]
    DIRECTION INPUT ;
    USE SIGNAL ;
    ANTENNAGATEAREA 0.196500 ;
    PORT
      LAYER met3 ;
        RECT 0.000 219.000 4.000 219.600 ;
    END
  END inputB[19]
  PIN inputB[1]
    DIRECTION INPUT ;
    USE SIGNAL ;
    ANTENNAGATEAREA 0.213000 ;
    PORT
      LAYER met3 ;
        RECT 0.000 170.040 4.000 170.640 ;
    END
  END inputB[1]
  PIN inputB[20]
    DIRECTION INPUT ;
    USE SIGNAL ;
    ANTENNAGATEAREA 0.196500 ;
    PORT
      LAYER met3 ;
        RECT 0.000 221.720 4.000 222.320 ;
    END
  END inputB[20]
  PIN inputB[21]
    DIRECTION INPUT ;
    USE SIGNAL ;
    ANTENNAGATEAREA 0.196500 ;
    PORT
      LAYER met3 ;
        RECT 0.000 224.440 4.000 225.040 ;
    END
  END inputB[21]
  PIN inputB[22]
    DIRECTION INPUT ;
    USE SIGNAL ;
    ANTENNAGATEAREA 0.196500 ;
    PORT
      LAYER met3 ;
        RECT 0.000 227.160 4.000 227.760 ;
    END
  END inputB[22]
  PIN inputB[23]
    DIRECTION INPUT ;
    USE SIGNAL ;
    ANTENNAGATEAREA 0.196500 ;
    PORT
      LAYER met3 ;
        RECT 0.000 229.880 4.000 230.480 ;
    END
  END inputB[23]
  PIN inputB[24]
    DIRECTION INPUT ;
    USE SIGNAL ;
    ANTENNAGATEAREA 0.196500 ;
    PORT
      LAYER met3 ;
        RECT 0.000 232.600 4.000 233.200 ;
    END
  END inputB[24]
  PIN inputB[25]
    DIRECTION INPUT ;
    USE SIGNAL ;
    ANTENNAGATEAREA 0.196500 ;
    PORT
      LAYER met3 ;
        RECT 0.000 235.320 4.000 235.920 ;
    END
  END inputB[25]
  PIN inputB[26]
    DIRECTION INPUT ;
    USE SIGNAL ;
    ANTENNAGATEAREA 0.196500 ;
    PORT
      LAYER met3 ;
        RECT 0.000 238.040 4.000 238.640 ;
    END
  END inputB[26]
  PIN inputB[27]
    DIRECTION INPUT ;
    USE SIGNAL ;
    ANTENNAGATEAREA 0.196500 ;
    PORT
      LAYER met3 ;
        RECT 0.000 240.760 4.000 241.360 ;
    END
  END inputB[27]
  PIN inputB[28]
    DIRECTION INPUT ;
    USE SIGNAL ;
    ANTENNAGATEAREA 0.196500 ;
    PORT
      LAYER met3 ;
        RECT 0.000 243.480 4.000 244.080 ;
    END
  END inputB[28]
  PIN inputB[29]
    DIRECTION INPUT ;
    USE SIGNAL ;
    ANTENNAGATEAREA 0.126000 ;
    PORT
      LAYER met3 ;
        RECT 0.000 246.200 4.000 246.800 ;
    END
  END inputB[29]
  PIN inputB[2]
    DIRECTION INPUT ;
    USE SIGNAL ;
    ANTENNAGATEAREA 0.159000 ;
    PORT
      LAYER met3 ;
        RECT 0.000 172.760 4.000 173.360 ;
    END
  END inputB[2]
  PIN inputB[30]
    DIRECTION INPUT ;
    USE SIGNAL ;
    ANTENNAGATEAREA 0.196500 ;
    PORT
      LAYER met3 ;
        RECT 0.000 248.920 4.000 249.520 ;
    END
  END inputB[30]
  PIN inputB[31]
    DIRECTION INPUT ;
    USE SIGNAL ;
    ANTENNAGATEAREA 0.196500 ;
    PORT
      LAYER met3 ;
        RECT 0.000 251.640 4.000 252.240 ;
    END
  END inputB[31]
  PIN inputB[3]
    DIRECTION INPUT ;
    USE SIGNAL ;
    ANTENNAGATEAREA 0.126000 ;
    PORT
      LAYER met3 ;
        RECT 0.000 175.480 4.000 176.080 ;
    END
  END inputB[3]
  PIN inputB[4]
    DIRECTION INPUT ;
    USE SIGNAL ;
    ANTENNAGATEAREA 0.159000 ;
    PORT
      LAYER met3 ;
        RECT 0.000 178.200 4.000 178.800 ;
    END
  END inputB[4]
  PIN inputB[5]
    DIRECTION INPUT ;
    USE SIGNAL ;
    ANTENNAGATEAREA 0.213000 ;
    PORT
      LAYER met3 ;
        RECT 0.000 180.920 4.000 181.520 ;
    END
  END inputB[5]
  PIN inputB[6]
    DIRECTION INPUT ;
    USE SIGNAL ;
    ANTENNAGATEAREA 0.196500 ;
    PORT
      LAYER met3 ;
        RECT 0.000 183.640 4.000 184.240 ;
    END
  END inputB[6]
  PIN inputB[7]
    DIRECTION INPUT ;
    USE SIGNAL ;
    ANTENNAGATEAREA 0.196500 ;
    PORT
      LAYER met3 ;
        RECT 0.000 186.360 4.000 186.960 ;
    END
  END inputB[7]
  PIN inputB[8]
    DIRECTION INPUT ;
    USE SIGNAL ;
    ANTENNAGATEAREA 0.196500 ;
    PORT
      LAYER met3 ;
        RECT 0.000 189.080 4.000 189.680 ;
    END
  END inputB[8]
  PIN inputB[9]
    DIRECTION INPUT ;
    USE SIGNAL ;
    ANTENNAGATEAREA 0.196500 ;
    PORT
      LAYER met3 ;
        RECT 0.000 191.800 4.000 192.400 ;
    END
  END inputB[9]
  PIN opcode[0]
    DIRECTION INPUT ;
    USE SIGNAL ;
    ANTENNAGATEAREA 0.213000 ;
    PORT
      LAYER met3 ;
        RECT 0.000 254.360 4.000 254.960 ;
    END
  END opcode[0]
  PIN opcode[1]
    DIRECTION INPUT ;
    USE SIGNAL ;
    ANTENNAGATEAREA 0.247500 ;
    PORT
      LAYER met3 ;
        RECT 0.000 257.080 4.000 257.680 ;
    END
  END opcode[1]
  PIN outputC[0]
    DIRECTION OUTPUT ;
    USE SIGNAL ;
    ANTENNADIFFAREA 0.445500 ;
    PORT
      LAYER met3 ;
        RECT 452.785 39.480 456.785 40.080 ;
    END
  END outputC[0]
  PIN outputC[10]
    DIRECTION OUTPUT ;
    USE SIGNAL ;
    ANTENNADIFFAREA 0.445500 ;
    PORT
      LAYER met3 ;
        RECT 452.785 80.280 456.785 80.880 ;
    END
  END outputC[10]
  PIN outputC[11]
    DIRECTION OUTPUT ;
    USE SIGNAL ;
    ANTENNADIFFAREA 0.445500 ;
    PORT
      LAYER met3 ;
        RECT 452.785 84.360 456.785 84.960 ;
    END
  END outputC[11]
  PIN outputC[12]
    DIRECTION OUTPUT ;
    USE SIGNAL ;
    ANTENNADIFFAREA 0.445500 ;
    PORT
      LAYER met3 ;
        RECT 452.785 88.440 456.785 89.040 ;
    END
  END outputC[12]
  PIN outputC[13]
    DIRECTION OUTPUT ;
    USE SIGNAL ;
    ANTENNADIFFAREA 0.445500 ;
    PORT
      LAYER met3 ;
        RECT 452.785 92.520 456.785 93.120 ;
    END
  END outputC[13]
  PIN outputC[14]
    DIRECTION OUTPUT ;
    USE SIGNAL ;
    ANTENNADIFFAREA 0.445500 ;
    PORT
      LAYER met3 ;
        RECT 452.785 96.600 456.785 97.200 ;
    END
  END outputC[14]
  PIN outputC[15]
    DIRECTION OUTPUT ;
    USE SIGNAL ;
    ANTENNADIFFAREA 0.445500 ;
    PORT
      LAYER met3 ;
        RECT 452.785 100.680 456.785 101.280 ;
    END
  END outputC[15]
  PIN outputC[16]
    DIRECTION OUTPUT ;
    USE SIGNAL ;
    ANTENNADIFFAREA 0.445500 ;
    PORT
      LAYER met3 ;
        RECT 452.785 104.760 456.785 105.360 ;
    END
  END outputC[16]
  PIN outputC[17]
    DIRECTION OUTPUT ;
    USE SIGNAL ;
    ANTENNADIFFAREA 0.445500 ;
    PORT
      LAYER met3 ;
        RECT 452.785 108.840 456.785 109.440 ;
    END
  END outputC[17]
  PIN outputC[18]
    DIRECTION OUTPUT ;
    USE SIGNAL ;
    ANTENNADIFFAREA 0.445500 ;
    PORT
      LAYER met3 ;
        RECT 452.785 112.920 456.785 113.520 ;
    END
  END outputC[18]
  PIN outputC[19]
    DIRECTION OUTPUT ;
    USE SIGNAL ;
    ANTENNADIFFAREA 0.445500 ;
    PORT
      LAYER met3 ;
        RECT 452.785 117.000 456.785 117.600 ;
    END
  END outputC[19]
  PIN outputC[1]
    DIRECTION OUTPUT ;
    USE SIGNAL ;
    ANTENNADIFFAREA 0.445500 ;
    PORT
      LAYER met3 ;
        RECT 452.785 43.560 456.785 44.160 ;
    END
  END outputC[1]
  PIN outputC[20]
    DIRECTION OUTPUT ;
    USE SIGNAL ;
    ANTENNADIFFAREA 0.445500 ;
    PORT
      LAYER met3 ;
        RECT 452.785 121.080 456.785 121.680 ;
    END
  END outputC[20]
  PIN outputC[21]
    DIRECTION OUTPUT ;
    USE SIGNAL ;
    ANTENNADIFFAREA 0.445500 ;
    PORT
      LAYER met3 ;
        RECT 452.785 125.160 456.785 125.760 ;
    END
  END outputC[21]
  PIN outputC[22]
    DIRECTION OUTPUT ;
    USE SIGNAL ;
    ANTENNADIFFAREA 0.445500 ;
    PORT
      LAYER met3 ;
        RECT 452.785 129.240 456.785 129.840 ;
    END
  END outputC[22]
  PIN outputC[23]
    DIRECTION OUTPUT ;
    USE SIGNAL ;
    ANTENNADIFFAREA 0.445500 ;
    PORT
      LAYER met3 ;
        RECT 452.785 133.320 456.785 133.920 ;
    END
  END outputC[23]
  PIN outputC[24]
    DIRECTION OUTPUT ;
    USE SIGNAL ;
    ANTENNADIFFAREA 0.445500 ;
    PORT
      LAYER met3 ;
        RECT 452.785 137.400 456.785 138.000 ;
    END
  END outputC[24]
  PIN outputC[25]
    DIRECTION OUTPUT ;
    USE SIGNAL ;
    ANTENNADIFFAREA 0.445500 ;
    PORT
      LAYER met3 ;
        RECT 452.785 141.480 456.785 142.080 ;
    END
  END outputC[25]
  PIN outputC[26]
    DIRECTION OUTPUT ;
    USE SIGNAL ;
    ANTENNADIFFAREA 0.445500 ;
    PORT
      LAYER met3 ;
        RECT 452.785 145.560 456.785 146.160 ;
    END
  END outputC[26]
  PIN outputC[27]
    DIRECTION OUTPUT ;
    USE SIGNAL ;
    ANTENNADIFFAREA 0.445500 ;
    PORT
      LAYER met3 ;
        RECT 452.785 149.640 456.785 150.240 ;
    END
  END outputC[27]
  PIN outputC[28]
    DIRECTION OUTPUT ;
    USE SIGNAL ;
    ANTENNADIFFAREA 0.445500 ;
    PORT
      LAYER met3 ;
        RECT 452.785 153.720 456.785 154.320 ;
    END
  END outputC[28]
  PIN outputC[29]
    DIRECTION OUTPUT ;
    USE SIGNAL ;
    ANTENNADIFFAREA 0.445500 ;
    PORT
      LAYER met3 ;
        RECT 452.785 157.800 456.785 158.400 ;
    END
  END outputC[29]
  PIN outputC[2]
    DIRECTION OUTPUT ;
    USE SIGNAL ;
    ANTENNADIFFAREA 0.445500 ;
    PORT
      LAYER met3 ;
        RECT 452.785 47.640 456.785 48.240 ;
    END
  END outputC[2]
  PIN outputC[30]
    DIRECTION OUTPUT ;
    USE SIGNAL ;
    ANTENNADIFFAREA 0.445500 ;
    PORT
      LAYER met3 ;
        RECT 452.785 161.880 456.785 162.480 ;
    END
  END outputC[30]
  PIN outputC[31]
    DIRECTION OUTPUT ;
    USE SIGNAL ;
    ANTENNADIFFAREA 0.445500 ;
    PORT
      LAYER met3 ;
        RECT 452.785 165.960 456.785 166.560 ;
    END
  END outputC[31]
  PIN outputC[3]
    DIRECTION OUTPUT ;
    USE SIGNAL ;
    ANTENNADIFFAREA 0.445500 ;
    PORT
      LAYER met3 ;
        RECT 452.785 51.720 456.785 52.320 ;
    END
  END outputC[3]
  PIN outputC[4]
    DIRECTION OUTPUT ;
    USE SIGNAL ;
    ANTENNADIFFAREA 0.445500 ;
    PORT
      LAYER met3 ;
        RECT 452.785 55.800 456.785 56.400 ;
    END
  END outputC[4]
  PIN outputC[5]
    DIRECTION OUTPUT ;
    USE SIGNAL ;
    ANTENNADIFFAREA 0.445500 ;
    PORT
      LAYER met3 ;
        RECT 452.785 59.880 456.785 60.480 ;
    END
  END outputC[5]
  PIN outputC[6]
    DIRECTION OUTPUT ;
    USE SIGNAL ;
    ANTENNADIFFAREA 0.445500 ;
    PORT
      LAYER met3 ;
        RECT 452.785 63.960 456.785 64.560 ;
    END
  END outputC[6]
  PIN outputC[7]
    DIRECTION OUTPUT ;
    USE SIGNAL ;
    ANTENNADIFFAREA 0.445500 ;
    PORT
      LAYER met3 ;
        RECT 452.785 68.040 456.785 68.640 ;
    END
  END outputC[7]
  PIN outputC[8]
    DIRECTION OUTPUT ;
    USE SIGNAL ;
    ANTENNADIFFAREA 0.445500 ;
    PORT
      LAYER met3 ;
        RECT 452.785 72.120 456.785 72.720 ;
    END
  END outputC[8]
  PIN outputC[9]
    DIRECTION OUTPUT ;
    USE SIGNAL ;
    ANTENNADIFFAREA 0.445500 ;
    PORT
      LAYER met3 ;
        RECT 452.785 76.200 456.785 76.800 ;
    END
  END outputC[9]
  OBS
      LAYER nwell ;
        RECT 5.330 10.795 451.450 454.430 ;
      LAYER li1 ;
        RECT 5.520 10.795 451.260 454.325 ;
      LAYER met1 ;
        RECT 4.210 10.640 454.870 454.880 ;
      LAYER met2 ;
        RECT 4.230 10.695 454.850 454.910 ;
      LAYER met3 ;
        RECT 3.750 428.080 454.875 454.405 ;
        RECT 3.750 426.680 452.385 428.080 ;
        RECT 3.750 424.000 454.875 426.680 ;
        RECT 3.750 422.600 452.385 424.000 ;
        RECT 3.750 419.920 454.875 422.600 ;
        RECT 3.750 418.520 452.385 419.920 ;
        RECT 3.750 415.840 454.875 418.520 ;
        RECT 3.750 414.440 452.385 415.840 ;
        RECT 3.750 411.760 454.875 414.440 ;
        RECT 3.750 410.360 452.385 411.760 ;
        RECT 3.750 407.680 454.875 410.360 ;
        RECT 3.750 406.280 452.385 407.680 ;
        RECT 3.750 403.600 454.875 406.280 ;
        RECT 3.750 402.200 452.385 403.600 ;
        RECT 3.750 399.520 454.875 402.200 ;
        RECT 3.750 398.120 452.385 399.520 ;
        RECT 3.750 395.440 454.875 398.120 ;
        RECT 3.750 394.040 452.385 395.440 ;
        RECT 3.750 391.360 454.875 394.040 ;
        RECT 3.750 389.960 452.385 391.360 ;
        RECT 3.750 388.640 454.875 389.960 ;
        RECT 4.400 387.280 454.875 388.640 ;
        RECT 4.400 387.240 452.385 387.280 ;
        RECT 3.750 385.920 452.385 387.240 ;
        RECT 4.400 385.880 452.385 385.920 ;
        RECT 4.400 384.520 454.875 385.880 ;
        RECT 3.750 383.200 454.875 384.520 ;
        RECT 4.400 381.800 452.385 383.200 ;
        RECT 3.750 380.480 454.875 381.800 ;
        RECT 4.400 379.120 454.875 380.480 ;
        RECT 4.400 379.080 452.385 379.120 ;
        RECT 3.750 377.760 452.385 379.080 ;
        RECT 4.400 377.720 452.385 377.760 ;
        RECT 4.400 376.360 454.875 377.720 ;
        RECT 3.750 375.040 454.875 376.360 ;
        RECT 4.400 373.640 452.385 375.040 ;
        RECT 3.750 372.320 454.875 373.640 ;
        RECT 4.400 370.960 454.875 372.320 ;
        RECT 4.400 370.920 452.385 370.960 ;
        RECT 3.750 369.600 452.385 370.920 ;
        RECT 4.400 369.560 452.385 369.600 ;
        RECT 4.400 368.200 454.875 369.560 ;
        RECT 3.750 366.880 454.875 368.200 ;
        RECT 4.400 365.480 452.385 366.880 ;
        RECT 3.750 364.160 454.875 365.480 ;
        RECT 4.400 362.800 454.875 364.160 ;
        RECT 4.400 362.760 452.385 362.800 ;
        RECT 3.750 361.440 452.385 362.760 ;
        RECT 4.400 361.400 452.385 361.440 ;
        RECT 4.400 360.040 454.875 361.400 ;
        RECT 3.750 358.720 454.875 360.040 ;
        RECT 4.400 357.320 452.385 358.720 ;
        RECT 3.750 356.000 454.875 357.320 ;
        RECT 4.400 354.640 454.875 356.000 ;
        RECT 4.400 354.600 452.385 354.640 ;
        RECT 3.750 353.280 452.385 354.600 ;
        RECT 4.400 353.240 452.385 353.280 ;
        RECT 4.400 351.880 454.875 353.240 ;
        RECT 3.750 350.560 454.875 351.880 ;
        RECT 4.400 349.160 452.385 350.560 ;
        RECT 3.750 347.840 454.875 349.160 ;
        RECT 4.400 346.480 454.875 347.840 ;
        RECT 4.400 346.440 452.385 346.480 ;
        RECT 3.750 345.120 452.385 346.440 ;
        RECT 4.400 345.080 452.385 345.120 ;
        RECT 4.400 343.720 454.875 345.080 ;
        RECT 3.750 342.400 454.875 343.720 ;
        RECT 4.400 341.000 452.385 342.400 ;
        RECT 3.750 339.680 454.875 341.000 ;
        RECT 4.400 338.320 454.875 339.680 ;
        RECT 4.400 338.280 452.385 338.320 ;
        RECT 3.750 336.960 452.385 338.280 ;
        RECT 4.400 336.920 452.385 336.960 ;
        RECT 4.400 335.560 454.875 336.920 ;
        RECT 3.750 334.240 454.875 335.560 ;
        RECT 4.400 332.840 452.385 334.240 ;
        RECT 3.750 331.520 454.875 332.840 ;
        RECT 4.400 330.160 454.875 331.520 ;
        RECT 4.400 330.120 452.385 330.160 ;
        RECT 3.750 328.800 452.385 330.120 ;
        RECT 4.400 328.760 452.385 328.800 ;
        RECT 4.400 327.400 454.875 328.760 ;
        RECT 3.750 326.080 454.875 327.400 ;
        RECT 4.400 324.680 452.385 326.080 ;
        RECT 3.750 323.360 454.875 324.680 ;
        RECT 4.400 322.000 454.875 323.360 ;
        RECT 4.400 321.960 452.385 322.000 ;
        RECT 3.750 320.640 452.385 321.960 ;
        RECT 4.400 320.600 452.385 320.640 ;
        RECT 4.400 319.240 454.875 320.600 ;
        RECT 3.750 317.920 454.875 319.240 ;
        RECT 4.400 316.520 452.385 317.920 ;
        RECT 3.750 315.200 454.875 316.520 ;
        RECT 4.400 313.840 454.875 315.200 ;
        RECT 4.400 313.800 452.385 313.840 ;
        RECT 3.750 312.480 452.385 313.800 ;
        RECT 4.400 312.440 452.385 312.480 ;
        RECT 4.400 311.080 454.875 312.440 ;
        RECT 3.750 309.760 454.875 311.080 ;
        RECT 4.400 308.360 452.385 309.760 ;
        RECT 3.750 307.040 454.875 308.360 ;
        RECT 4.400 305.680 454.875 307.040 ;
        RECT 4.400 305.640 452.385 305.680 ;
        RECT 3.750 304.320 452.385 305.640 ;
        RECT 4.400 304.280 452.385 304.320 ;
        RECT 4.400 302.920 454.875 304.280 ;
        RECT 3.750 301.600 454.875 302.920 ;
        RECT 4.400 300.200 452.385 301.600 ;
        RECT 3.750 298.880 454.875 300.200 ;
        RECT 4.400 297.520 454.875 298.880 ;
        RECT 4.400 297.480 452.385 297.520 ;
        RECT 3.750 296.160 452.385 297.480 ;
        RECT 4.400 296.120 452.385 296.160 ;
        RECT 4.400 294.760 454.875 296.120 ;
        RECT 3.750 293.440 454.875 294.760 ;
        RECT 4.400 292.040 452.385 293.440 ;
        RECT 3.750 290.720 454.875 292.040 ;
        RECT 4.400 289.360 454.875 290.720 ;
        RECT 4.400 289.320 452.385 289.360 ;
        RECT 3.750 288.000 452.385 289.320 ;
        RECT 4.400 287.960 452.385 288.000 ;
        RECT 4.400 286.600 454.875 287.960 ;
        RECT 3.750 285.280 454.875 286.600 ;
        RECT 4.400 283.880 452.385 285.280 ;
        RECT 3.750 282.560 454.875 283.880 ;
        RECT 4.400 281.200 454.875 282.560 ;
        RECT 4.400 281.160 452.385 281.200 ;
        RECT 3.750 279.840 452.385 281.160 ;
        RECT 4.400 279.800 452.385 279.840 ;
        RECT 4.400 278.440 454.875 279.800 ;
        RECT 3.750 277.120 454.875 278.440 ;
        RECT 4.400 275.720 452.385 277.120 ;
        RECT 3.750 274.400 454.875 275.720 ;
        RECT 4.400 273.040 454.875 274.400 ;
        RECT 4.400 273.000 452.385 273.040 ;
        RECT 3.750 271.680 452.385 273.000 ;
        RECT 4.400 271.640 452.385 271.680 ;
        RECT 4.400 270.280 454.875 271.640 ;
        RECT 3.750 268.960 454.875 270.280 ;
        RECT 4.400 267.560 452.385 268.960 ;
        RECT 3.750 266.240 454.875 267.560 ;
        RECT 4.400 264.880 454.875 266.240 ;
        RECT 4.400 264.840 452.385 264.880 ;
        RECT 3.750 263.520 452.385 264.840 ;
        RECT 4.400 263.480 452.385 263.520 ;
        RECT 4.400 262.120 454.875 263.480 ;
        RECT 3.750 260.800 454.875 262.120 ;
        RECT 4.400 259.400 452.385 260.800 ;
        RECT 3.750 258.080 454.875 259.400 ;
        RECT 4.400 256.720 454.875 258.080 ;
        RECT 4.400 256.680 452.385 256.720 ;
        RECT 3.750 255.360 452.385 256.680 ;
        RECT 4.400 255.320 452.385 255.360 ;
        RECT 4.400 253.960 454.875 255.320 ;
        RECT 3.750 252.640 454.875 253.960 ;
        RECT 4.400 251.240 452.385 252.640 ;
        RECT 3.750 249.920 454.875 251.240 ;
        RECT 4.400 248.560 454.875 249.920 ;
        RECT 4.400 248.520 452.385 248.560 ;
        RECT 3.750 247.200 452.385 248.520 ;
        RECT 4.400 247.160 452.385 247.200 ;
        RECT 4.400 245.800 454.875 247.160 ;
        RECT 3.750 244.480 454.875 245.800 ;
        RECT 4.400 243.080 452.385 244.480 ;
        RECT 3.750 241.760 454.875 243.080 ;
        RECT 4.400 240.400 454.875 241.760 ;
        RECT 4.400 240.360 452.385 240.400 ;
        RECT 3.750 239.040 452.385 240.360 ;
        RECT 4.400 239.000 452.385 239.040 ;
        RECT 4.400 237.640 454.875 239.000 ;
        RECT 3.750 236.320 454.875 237.640 ;
        RECT 4.400 234.920 452.385 236.320 ;
        RECT 3.750 233.600 454.875 234.920 ;
        RECT 4.400 232.240 454.875 233.600 ;
        RECT 4.400 232.200 452.385 232.240 ;
        RECT 3.750 230.880 452.385 232.200 ;
        RECT 4.400 230.840 452.385 230.880 ;
        RECT 4.400 229.480 454.875 230.840 ;
        RECT 3.750 228.160 454.875 229.480 ;
        RECT 4.400 226.760 452.385 228.160 ;
        RECT 3.750 225.440 454.875 226.760 ;
        RECT 4.400 224.080 454.875 225.440 ;
        RECT 4.400 224.040 452.385 224.080 ;
        RECT 3.750 222.720 452.385 224.040 ;
        RECT 4.400 222.680 452.385 222.720 ;
        RECT 4.400 221.320 454.875 222.680 ;
        RECT 3.750 220.000 454.875 221.320 ;
        RECT 4.400 218.600 452.385 220.000 ;
        RECT 3.750 217.280 454.875 218.600 ;
        RECT 4.400 215.920 454.875 217.280 ;
        RECT 4.400 215.880 452.385 215.920 ;
        RECT 3.750 214.560 452.385 215.880 ;
        RECT 4.400 214.520 452.385 214.560 ;
        RECT 4.400 213.160 454.875 214.520 ;
        RECT 3.750 211.840 454.875 213.160 ;
        RECT 4.400 210.440 452.385 211.840 ;
        RECT 3.750 209.120 454.875 210.440 ;
        RECT 4.400 207.760 454.875 209.120 ;
        RECT 4.400 207.720 452.385 207.760 ;
        RECT 3.750 206.400 452.385 207.720 ;
        RECT 4.400 206.360 452.385 206.400 ;
        RECT 4.400 205.000 454.875 206.360 ;
        RECT 3.750 203.680 454.875 205.000 ;
        RECT 4.400 202.280 452.385 203.680 ;
        RECT 3.750 200.960 454.875 202.280 ;
        RECT 4.400 199.600 454.875 200.960 ;
        RECT 4.400 199.560 452.385 199.600 ;
        RECT 3.750 198.240 452.385 199.560 ;
        RECT 4.400 198.200 452.385 198.240 ;
        RECT 4.400 196.840 454.875 198.200 ;
        RECT 3.750 195.520 454.875 196.840 ;
        RECT 4.400 194.120 452.385 195.520 ;
        RECT 3.750 192.800 454.875 194.120 ;
        RECT 4.400 191.440 454.875 192.800 ;
        RECT 4.400 191.400 452.385 191.440 ;
        RECT 3.750 190.080 452.385 191.400 ;
        RECT 4.400 190.040 452.385 190.080 ;
        RECT 4.400 188.680 454.875 190.040 ;
        RECT 3.750 187.360 454.875 188.680 ;
        RECT 4.400 185.960 452.385 187.360 ;
        RECT 3.750 184.640 454.875 185.960 ;
        RECT 4.400 183.280 454.875 184.640 ;
        RECT 4.400 183.240 452.385 183.280 ;
        RECT 3.750 181.920 452.385 183.240 ;
        RECT 4.400 181.880 452.385 181.920 ;
        RECT 4.400 180.520 454.875 181.880 ;
        RECT 3.750 179.200 454.875 180.520 ;
        RECT 4.400 177.800 452.385 179.200 ;
        RECT 3.750 176.480 454.875 177.800 ;
        RECT 4.400 175.120 454.875 176.480 ;
        RECT 4.400 175.080 452.385 175.120 ;
        RECT 3.750 173.760 452.385 175.080 ;
        RECT 4.400 173.720 452.385 173.760 ;
        RECT 4.400 172.360 454.875 173.720 ;
        RECT 3.750 171.040 454.875 172.360 ;
        RECT 4.400 169.640 452.385 171.040 ;
        RECT 3.750 168.320 454.875 169.640 ;
        RECT 4.400 166.960 454.875 168.320 ;
        RECT 4.400 166.920 452.385 166.960 ;
        RECT 3.750 165.600 452.385 166.920 ;
        RECT 4.400 165.560 452.385 165.600 ;
        RECT 4.400 164.200 454.875 165.560 ;
        RECT 3.750 162.880 454.875 164.200 ;
        RECT 4.400 161.480 452.385 162.880 ;
        RECT 3.750 160.160 454.875 161.480 ;
        RECT 4.400 158.800 454.875 160.160 ;
        RECT 4.400 158.760 452.385 158.800 ;
        RECT 3.750 157.440 452.385 158.760 ;
        RECT 4.400 157.400 452.385 157.440 ;
        RECT 4.400 156.040 454.875 157.400 ;
        RECT 3.750 154.720 454.875 156.040 ;
        RECT 4.400 153.320 452.385 154.720 ;
        RECT 3.750 152.000 454.875 153.320 ;
        RECT 4.400 150.640 454.875 152.000 ;
        RECT 4.400 150.600 452.385 150.640 ;
        RECT 3.750 149.280 452.385 150.600 ;
        RECT 4.400 149.240 452.385 149.280 ;
        RECT 4.400 147.880 454.875 149.240 ;
        RECT 3.750 146.560 454.875 147.880 ;
        RECT 4.400 145.160 452.385 146.560 ;
        RECT 3.750 143.840 454.875 145.160 ;
        RECT 4.400 142.480 454.875 143.840 ;
        RECT 4.400 142.440 452.385 142.480 ;
        RECT 3.750 141.120 452.385 142.440 ;
        RECT 4.400 141.080 452.385 141.120 ;
        RECT 4.400 139.720 454.875 141.080 ;
        RECT 3.750 138.400 454.875 139.720 ;
        RECT 4.400 137.000 452.385 138.400 ;
        RECT 3.750 135.680 454.875 137.000 ;
        RECT 4.400 134.320 454.875 135.680 ;
        RECT 4.400 134.280 452.385 134.320 ;
        RECT 3.750 132.960 452.385 134.280 ;
        RECT 4.400 132.920 452.385 132.960 ;
        RECT 4.400 131.560 454.875 132.920 ;
        RECT 3.750 130.240 454.875 131.560 ;
        RECT 4.400 128.840 452.385 130.240 ;
        RECT 3.750 127.520 454.875 128.840 ;
        RECT 4.400 126.160 454.875 127.520 ;
        RECT 4.400 126.120 452.385 126.160 ;
        RECT 3.750 124.800 452.385 126.120 ;
        RECT 4.400 124.760 452.385 124.800 ;
        RECT 4.400 123.400 454.875 124.760 ;
        RECT 3.750 122.080 454.875 123.400 ;
        RECT 4.400 120.680 452.385 122.080 ;
        RECT 3.750 119.360 454.875 120.680 ;
        RECT 4.400 118.000 454.875 119.360 ;
        RECT 4.400 117.960 452.385 118.000 ;
        RECT 3.750 116.640 452.385 117.960 ;
        RECT 4.400 116.600 452.385 116.640 ;
        RECT 4.400 115.240 454.875 116.600 ;
        RECT 3.750 113.920 454.875 115.240 ;
        RECT 4.400 112.520 452.385 113.920 ;
        RECT 3.750 111.200 454.875 112.520 ;
        RECT 4.400 109.840 454.875 111.200 ;
        RECT 4.400 109.800 452.385 109.840 ;
        RECT 3.750 108.480 452.385 109.800 ;
        RECT 4.400 108.440 452.385 108.480 ;
        RECT 4.400 107.080 454.875 108.440 ;
        RECT 3.750 105.760 454.875 107.080 ;
        RECT 4.400 104.360 452.385 105.760 ;
        RECT 3.750 103.040 454.875 104.360 ;
        RECT 4.400 101.680 454.875 103.040 ;
        RECT 4.400 101.640 452.385 101.680 ;
        RECT 3.750 100.320 452.385 101.640 ;
        RECT 4.400 100.280 452.385 100.320 ;
        RECT 4.400 98.920 454.875 100.280 ;
        RECT 3.750 97.600 454.875 98.920 ;
        RECT 4.400 96.200 452.385 97.600 ;
        RECT 3.750 94.880 454.875 96.200 ;
        RECT 4.400 93.520 454.875 94.880 ;
        RECT 4.400 93.480 452.385 93.520 ;
        RECT 3.750 92.160 452.385 93.480 ;
        RECT 4.400 92.120 452.385 92.160 ;
        RECT 4.400 90.760 454.875 92.120 ;
        RECT 3.750 89.440 454.875 90.760 ;
        RECT 4.400 88.040 452.385 89.440 ;
        RECT 3.750 86.720 454.875 88.040 ;
        RECT 4.400 85.360 454.875 86.720 ;
        RECT 4.400 85.320 452.385 85.360 ;
        RECT 3.750 84.000 452.385 85.320 ;
        RECT 4.400 83.960 452.385 84.000 ;
        RECT 4.400 82.600 454.875 83.960 ;
        RECT 3.750 81.280 454.875 82.600 ;
        RECT 4.400 79.880 452.385 81.280 ;
        RECT 3.750 78.560 454.875 79.880 ;
        RECT 4.400 77.200 454.875 78.560 ;
        RECT 4.400 77.160 452.385 77.200 ;
        RECT 3.750 75.800 452.385 77.160 ;
        RECT 3.750 73.120 454.875 75.800 ;
        RECT 3.750 71.720 452.385 73.120 ;
        RECT 3.750 69.040 454.875 71.720 ;
        RECT 3.750 67.640 452.385 69.040 ;
        RECT 3.750 64.960 454.875 67.640 ;
        RECT 3.750 63.560 452.385 64.960 ;
        RECT 3.750 60.880 454.875 63.560 ;
        RECT 3.750 59.480 452.385 60.880 ;
        RECT 3.750 56.800 454.875 59.480 ;
        RECT 3.750 55.400 452.385 56.800 ;
        RECT 3.750 52.720 454.875 55.400 ;
        RECT 3.750 51.320 452.385 52.720 ;
        RECT 3.750 48.640 454.875 51.320 ;
        RECT 3.750 47.240 452.385 48.640 ;
        RECT 3.750 44.560 454.875 47.240 ;
        RECT 3.750 43.160 452.385 44.560 ;
        RECT 3.750 40.480 454.875 43.160 ;
        RECT 3.750 39.080 452.385 40.480 ;
        RECT 3.750 10.715 454.875 39.080 ;
      LAYER met4 ;
        RECT 3.975 77.695 9.320 452.025 ;
        RECT 11.720 77.695 12.620 452.025 ;
        RECT 15.020 77.695 34.320 452.025 ;
        RECT 36.720 77.695 37.620 452.025 ;
        RECT 40.020 77.695 59.320 452.025 ;
        RECT 61.720 77.695 62.620 452.025 ;
        RECT 65.020 77.695 84.320 452.025 ;
        RECT 86.720 77.695 87.620 452.025 ;
        RECT 90.020 77.695 109.320 452.025 ;
        RECT 111.720 77.695 112.620 452.025 ;
        RECT 115.020 77.695 134.320 452.025 ;
        RECT 136.720 77.695 137.620 452.025 ;
        RECT 140.020 77.695 159.320 452.025 ;
        RECT 161.720 77.695 162.620 452.025 ;
        RECT 165.020 77.695 184.320 452.025 ;
        RECT 186.720 77.695 187.620 452.025 ;
        RECT 190.020 77.695 209.320 452.025 ;
        RECT 211.720 77.695 212.620 452.025 ;
        RECT 215.020 77.695 234.320 452.025 ;
        RECT 236.720 77.695 237.620 452.025 ;
        RECT 240.020 77.695 259.320 452.025 ;
        RECT 261.720 77.695 262.620 452.025 ;
        RECT 265.020 77.695 284.320 452.025 ;
        RECT 286.720 77.695 287.620 452.025 ;
        RECT 290.020 77.695 309.320 452.025 ;
        RECT 311.720 77.695 312.620 452.025 ;
        RECT 315.020 77.695 334.320 452.025 ;
        RECT 336.720 77.695 337.620 452.025 ;
        RECT 340.020 77.695 359.320 452.025 ;
        RECT 361.720 77.695 362.620 452.025 ;
        RECT 365.020 77.695 384.320 452.025 ;
        RECT 386.720 77.695 387.620 452.025 ;
        RECT 390.020 77.695 409.320 452.025 ;
        RECT 411.720 77.695 412.620 452.025 ;
        RECT 415.020 77.695 434.320 452.025 ;
        RECT 436.720 77.695 437.620 452.025 ;
        RECT 440.020 77.695 447.745 452.025 ;
      LAYER met5 ;
        RECT 7.940 396.580 442.860 403.700 ;
        RECT 7.940 371.580 442.860 388.480 ;
        RECT 7.940 346.580 442.860 363.480 ;
        RECT 7.940 321.580 442.860 338.480 ;
        RECT 7.940 296.580 442.860 313.480 ;
        RECT 7.940 271.580 442.860 288.480 ;
        RECT 7.940 246.580 442.860 263.480 ;
        RECT 7.940 221.580 442.860 238.480 ;
        RECT 7.940 196.580 442.860 213.480 ;
        RECT 7.940 171.580 442.860 188.480 ;
        RECT 7.940 153.900 442.860 163.480 ;
  END
END TopModule
END LIBRARY

